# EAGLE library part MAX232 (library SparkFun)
RS232 Transceiver Very common IC. This is generically called 'MAX232', but works with the 3V equivalent MAX3232 generic ICs. Field tested and mother approved. Spark Fun Electronics SKU : COM-00316 (DIP) and COM-00589 (SMD)

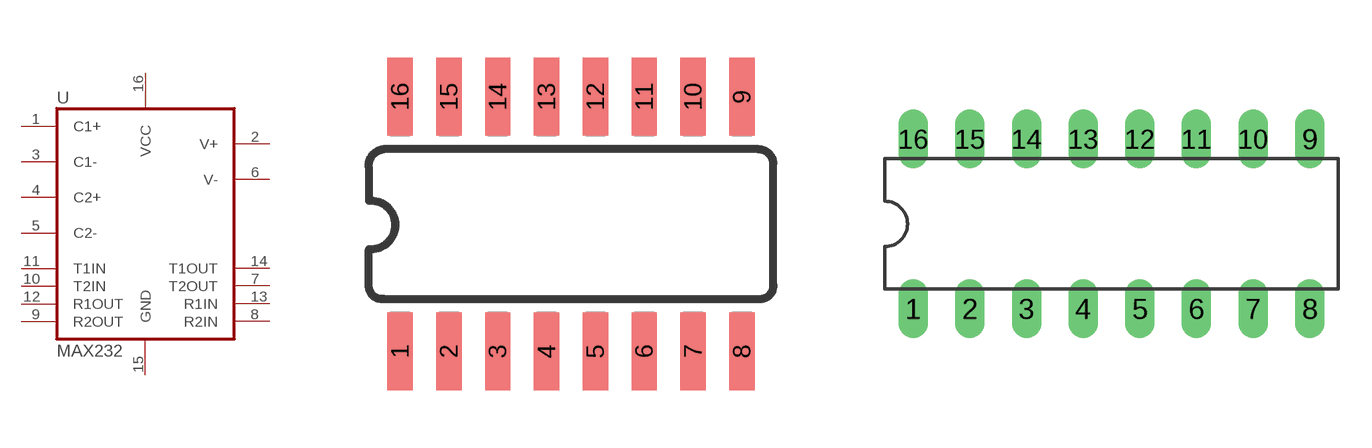
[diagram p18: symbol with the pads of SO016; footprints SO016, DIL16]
Designator prefix U

## MAX232SOIC16  [SO016]
1  C1+
2  V+
3  C1-
4  C2+
5  C2-
6  V-
7  T2OUT  out
8  R2IN  in
9  R2OUT  out
10  T2IN  in
11  T1IN  in
12  R1OUT  out
13  R1IN  in
14  T1OUT  out
15  GND
16  VCC

## MAX232PTH  [DIL16]
Pads as for SO016

## Footprint SO016 (pad centres in mm)
smd 0.66 x 2.032: 1 -4.445,-3.315; 2 -3.175,-3.315; 3 -1.905,-3.315; 4 -0.635,-3.315; 5 0.635,-3.315; 6 1.905,-3.315; 7 3.175,-3.315; 8 4.445,-3.315; 9 4.445,3.315; 10 3.175,3.315; 11 1.905,3.315; 12 0.635,3.315; 13 -0.635,3.315; 14 -1.905,3.315; 15 -3.175,3.315; 16 -4.445,3.315

## Footprint DIL16 (pad centres in mm)
Dual In Line Package
drill 0.813 long: 1 -8.89,-3.81; 2 -6.35,-3.81; 3 -3.81,-3.81; 4 -1.27,-3.81; 5 1.27,-3.81; 6 3.81,-3.81; 7 6.35,-3.81; 8 8.89,-3.81; 9 8.89,3.81; 10 6.35,3.81; 11 3.81,3.81; 12 1.27,3.81; 13 -1.27,3.81; 14 -3.81,3.81; 15 -6.35,3.81; 16 -8.89,3.81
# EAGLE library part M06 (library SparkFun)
Header 6 Standard 6-pin 0.1" header. Use with straight break away headers (SKU : PRT-00116), right angle break away headers (PRT-00553), swiss pins (PRT-00743), machine pins (PRT-00117), and female headers (PRT-00115). Molex polarized connector foot print use with SKU : PRT-08094 with associated crimp pins and housings.

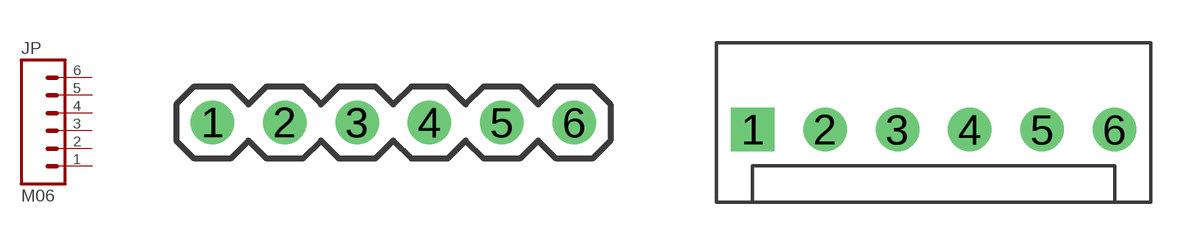
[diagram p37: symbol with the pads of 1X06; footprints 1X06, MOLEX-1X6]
Designator prefix JP

## M06SIP  [1X06]
1  1  pas
2  2  pas
3  3  pas
4  4  pas
5  5  pas
6  6  pas

## M06POL  [MOLEX-1X6]
Pads as for 1X06

## M06RA  [MOLEX-1X6-RA]
Pads as for 1X06

## Footprint 1X06 (pad centres in mm)
drill 1.016 round: 1 0,0; 2 2.54,0; 3 5.08,0; 4 7.62,0; 5 10.16,0; 6 12.7,0

## Footprint MOLEX-1X6 (pad centres in mm)
drill 1.016 square: 1 0,0
drill 1.016 round: 2 2.54,0; 3 5.08,0; 4 7.62,0; 5 10.16,0; 6 12.7,0

## Footprint MOLEX-1X6-RA (pad centres in mm)
drill 1.016 square: 1 0,0
drill 1.016 round: 2 2.54,0; 3 5.08,0; 4 7.62,0; 5 10.16,0; 6 12.7,0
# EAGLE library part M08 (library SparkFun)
Header 8 Standard 8-pin 0.1" header. Use with straight break away headers (SKU : PRT-00116), right angle break away headers (PRT-00553), swiss pins (PRT-00743), machine pins (PRT-00117), and female headers (PRT-00115).

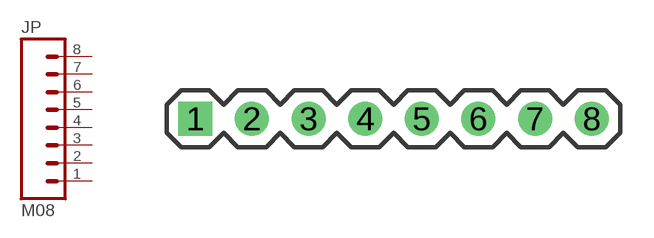
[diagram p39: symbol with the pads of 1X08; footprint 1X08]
Designator prefix JP

## M08  [1X08]
1  1  pas
2  2  pas
3  3  pas
4  4  pas
5  5  pas
6  6  pas
7  7  pas
8  8  pas

## Footprint 1X08 (pad centres in mm)
drill 1.016 square: 1 0,0
drill 1.016 round: 2 2.54,0; 3 5.08,0; 4 7.62,0; 5 10.16,0; 6 12.7,0; 7 15.24,0; 8 17.78,0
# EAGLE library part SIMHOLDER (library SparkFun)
SIM Socket Socket for SIM cellular cards. Schematic element and footprint production proven. Spark Fun Electronics SKU : PRT-00548

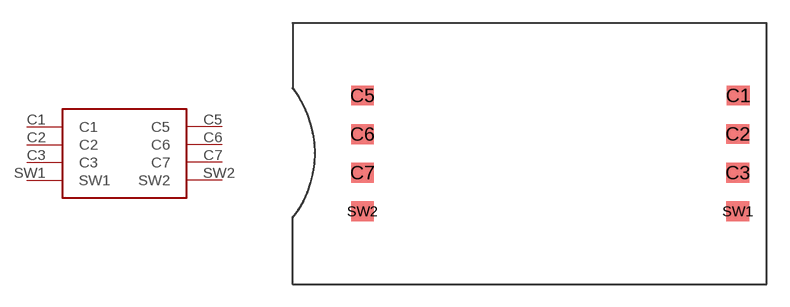
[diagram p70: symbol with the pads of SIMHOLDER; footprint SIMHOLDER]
Designator prefix -

## SIMHOLDER  [SIMHOLDER]
C1  C1
C2  C2
C3  C3
C5  C5
C6  C6
C7  C7
SW1  SW1
SW2  SW2

## Footprint SIMHOLDER (pad centres in mm)
smd 1.5 x 1.3: C1 24.73,0; C2 24.7,-2.53; C3 24.7,-5.08; C5 0,0; C6 0,-2.54; C7 0,-5.08; SW1 24.7,-7.62; SW2 0,-7.62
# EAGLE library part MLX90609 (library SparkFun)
Melexis Gyroscope MLX90609 Proven footprint and schematic for single axis MEMs gyroscope. Spark Fun Electronics SKU: COM-08336 and others

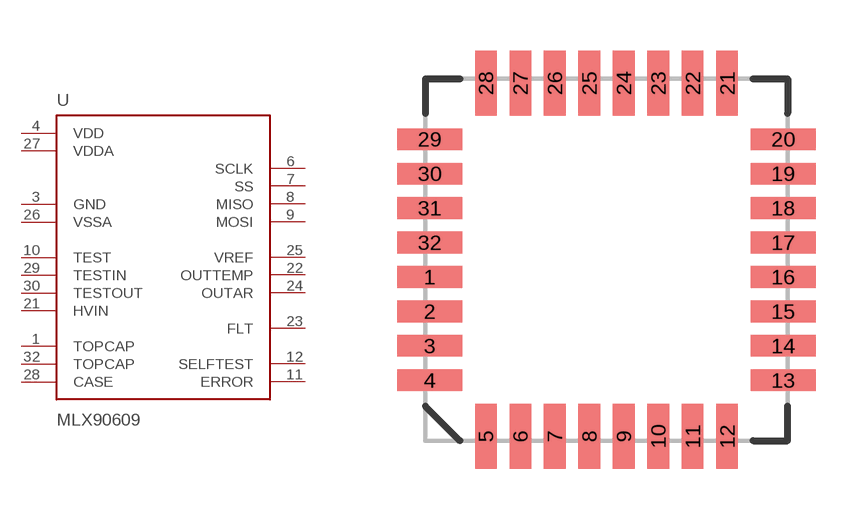
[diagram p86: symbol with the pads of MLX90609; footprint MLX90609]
Designator prefix -

## MLX90609SMD  [MLX90609]
1  TOPCAP
3  GND
4  VDD
6  SCLK
7  SS
8  MISO
9  MOSI
10  TEST
11  ERROR
12  SELFTEST
21  HVIN
22  OUTTEMP
23  FLT
24  OUTAR
25  VREF
26  VSSA
27  VDDA
28  CASE
29  TESTIN
30  TESTOUT
32  TOPCAP

## Footprint MLX90609 (pad centres in mm)
smd 1.905 x 0.635: 1 -5.207,-0.508; 2 -5.207,-1.524; 3 -5.207,-2.54; 4 -5.207,-3.556; 13 5.207,-3.556; 14 5.207,-2.54; 15 5.207,-1.524; 16 5.207,-0.508; 17 5.207,0.508; 18 5.207,1.524; 19 5.207,2.54; 20 5.207,3.556; 29 -5.207,3.556; 30 -5.207,2.54; 31 -5.207,1.524; 32 -5.207,0.508
smd 0.635 x 1.905: 5 -3.556,-5.207; 6 -2.54,-5.207; 7 -1.524,-5.207; 8 -0.508,-5.207; 9 0.508,-5.207; 10 1.524,-5.207; 11 2.54,-5.207; 12 3.556,-5.207; 21 3.556,5.207; 22 2.54,5.207; 23 1.524,5.207; 24 0.508,5.207; 25 -0.508,5.207; 26 -1.524,5.207; 27 -2.54,5.207; 28 -3.556,5.207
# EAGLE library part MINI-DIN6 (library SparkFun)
mini DIN 6 Connector Commonly found on the back of a computer for PS2 keyboard and mice. Schematic and footprint are proven. Spark Fun Electronics SKU : PRT-08509

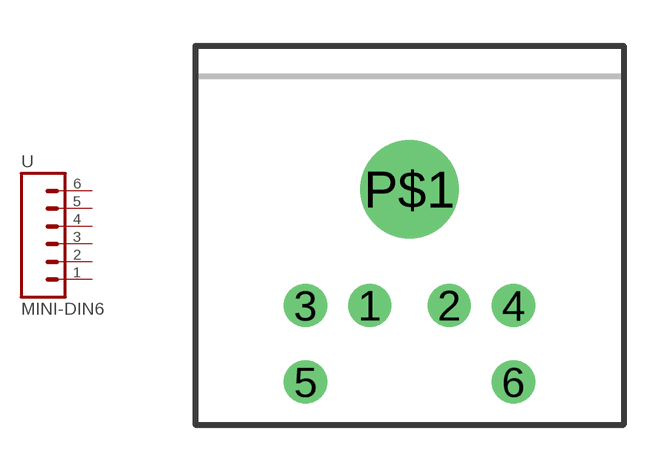
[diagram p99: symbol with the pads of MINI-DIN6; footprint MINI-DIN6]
Designator prefix -

## MINI-DIN6PTH  [MINI-DIN6]
1  1  pas
2  2  pas
3  3  pas
4  4  pas
5  5  pas
6  6  pas

## Footprint MINI-DIN6 (pad centres in mm)
drill 0.9 round: 1 -1.3,-8.5; 2 1.3,-8.5; 3 -3.4,-8.5; 4 3.4,-8.5; 5 -3.4,-11; 6 3.4,-11
drill 2.2 round: P$1 0,-4.7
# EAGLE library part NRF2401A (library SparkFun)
2.4GHz Transceiver This is the very popular, low power RF transceiver from Nordic Semiconductor. Used in the Nike+iPod product. SKU: COM-00300

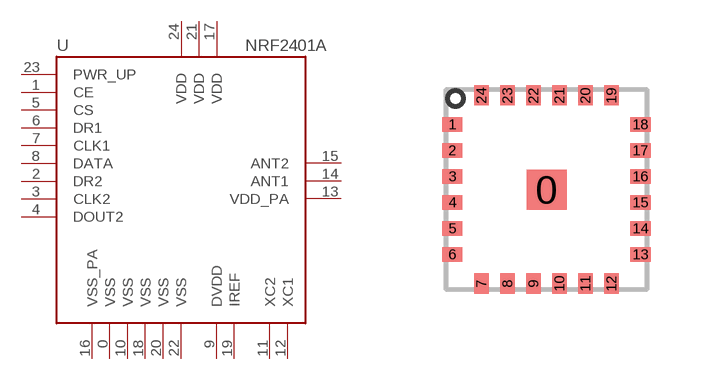
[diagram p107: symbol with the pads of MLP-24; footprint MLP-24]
Designator prefix -

## NRF2401ASMD  [MLP-24]
0  VSS  pwr
1  CE  in
2  DR2  out
3  CLK2
4  DOUT2  out
5  CS  in
6  DR1  out
7  CLK1
8  DATA
9  DVDD  pwr
10  VSS  pwr
11  XC2  in
12  XC1  in
13  VDD_PA  pwr
14  ANT1  out
15  ANT2  out
16  VSS_PA  pwr
17  VDD  pwr
18  VSS  pwr
19  IREF  in
20  VSS  pwr
21  VDD  pwr
22  VSS  pwr
23  PWR_UP  pwr
24  VDD  pwr

## Footprint MLP-24 (pad centres in mm)
smd 1 x 1: 0 0,0
smd 0.5 x 0.37: 1 -2.35,1.625; 2 -2.35,0.975; 3 -2.35,0.325; 4 -2.35,-0.325; 5 -2.35,-0.975; 6 -2.35,-1.625; 13 2.35,-1.625; 14 2.35,-0.975; 15 2.35,-0.325; 16 2.35,0.325; 17 2.35,0.975; 18 2.35,1.625
smd 0.37 x 0.5: 7 -1.625,-2.35; 8 -0.975,-2.35; 9 -0.325,-2.35; 10 0.325,-2.35; 11 0.975,-2.35; 12 1.625,-2.35; 19 1.625,2.35; 20 0.975,2.35; 21 0.325,2.35; 22 -0.325,2.35; 23 -0.975,2.35; 24 -1.625,2.35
